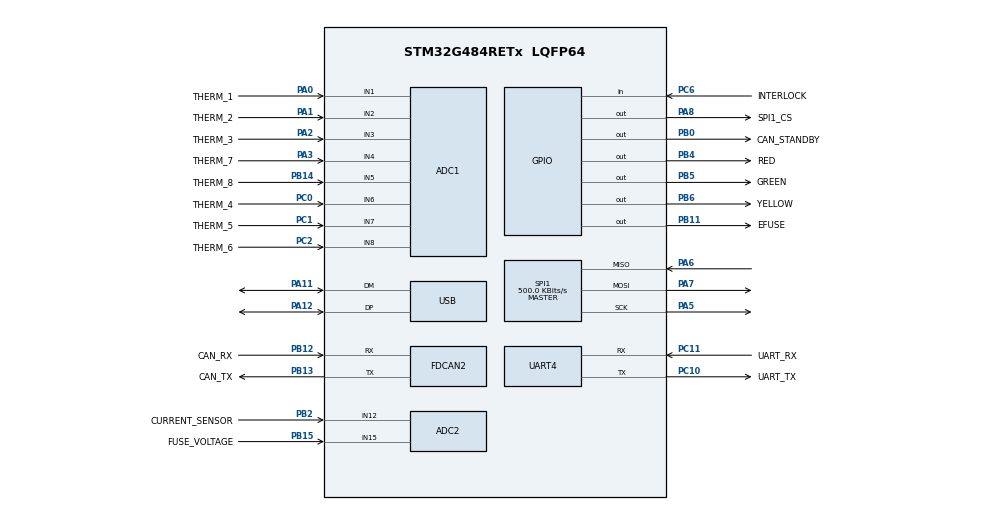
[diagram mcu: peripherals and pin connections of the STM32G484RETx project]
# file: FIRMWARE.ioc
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ADC1.Channel-0\#ChannelRegularConversion=ADC_CHANNEL_1
ADC1.Channel-1\#ChannelRegularConversion=ADC_CHANNEL_2
ADC1.Channel-2\#ChannelRegularConversion=ADC_CHANNEL_3
ADC1.Channel-3\#ChannelRegularConversion=ADC_CHANNEL_4
ADC1.Channel-4\#ChannelRegularConversion=ADC_CHANNEL_5
ADC1.Channel-5\#ChannelRegularConversion=ADC_CHANNEL_6
ADC1.Channel-6\#ChannelRegularConversion=ADC_CHANNEL_7
ADC1.Channel-7\#ChannelRegularConversion=ADC_CHANNEL_8
ADC1.ClockPrescaler=ADC_CLOCK_ASYNC_DIV4
ADC1.ContinuousConvMode=ENABLE
ADC1.DMAContinuousRequests=ENABLE
ADC1.NbrOfConversion=8
ADC1.NbrOfConversionFlag=1
ADC1.OffsetNumber-0\#ChannelRegularConversion=ADC_OFFSET_NONE
ADC1.OffsetNumber-1\#ChannelRegularConversion=ADC_OFFSET_NONE
ADC1.OffsetNumber-2\#ChannelRegularConversion=ADC_OFFSET_NONE
ADC1.OffsetNumber-3\#ChannelRegularConversion=ADC_OFFSET_NONE
ADC1.OffsetNumber-4\#ChannelRegularConversion=ADC_OFFSET_NONE
ADC1.OffsetNumber-5\#ChannelRegularConversion=ADC_OFFSET_NONE
ADC1.OffsetNumber-6\#ChannelRegularConversion=ADC_OFFSET_NONE
ADC1.OffsetNumber-7\#ChannelRegularConversion=ADC_OFFSET_NONE
ADC1.Rank-0\#ChannelRegularConversion=1
ADC1.Rank-1\#ChannelRegularConversion=2
ADC1.Rank-2\#ChannelRegularConversion=3
ADC1.Rank-3\#ChannelRegularConversion=4
ADC1.Rank-4\#ChannelRegularConversion=5
ADC1.Rank-5\#ChannelRegularConversion=6
ADC1.Rank-6\#ChannelRegularConversion=7
ADC1.Rank-7\#ChannelRegularConversion=8
ADC1.SamplingTime-0\#ChannelRegularConversion=ADC_SAMPLETIME_247CYCLES_5
ADC1.SamplingTime-1\#ChannelRegularConversion=ADC_SAMPLETIME_247CYCLES_5
ADC1.SamplingTime-2\#ChannelRegularConversion=ADC_SAMPLETIME_247CYCLES_5
ADC1.SamplingTime-3\#ChannelRegularConversion=ADC_SAMPLETIME_247CYCLES_5
ADC1.SamplingTime-4\#ChannelRegularConversion=ADC_SAMPLETIME_2CYCLES_5
ADC1.SamplingTime-5\#ChannelRegularConversion=ADC_SAMPLETIME_247CYCLES_5
ADC1.SamplingTime-6\#ChannelRegularConversion=ADC_SAMPLETIME_247CYCLES_5
ADC1.SamplingTime-7\#ChannelRegularConversion=ADC_SAMPLETIME_247CYCLES_5
ADC1.master=1
ADC2.Channel-0\#ChannelRegularConversion=ADC_CHANNEL_15
ADC2.Channel-1\#ChannelRegularConversion=ADC_CHANNEL_12
ADC2.ClockPrescaler=ADC_CLOCK_ASYNC_DIV4
ADC2.ContinuousConvMode=ENABLE
ADC2.DMAContinuousRequests=ENABLE
ADC2.NbrOfConversion=2
ADC2.NbrOfConversionFlag=1
ADC2.OffsetNumber-0\#ChannelRegularConversion=ADC_OFFSET_NONE
ADC2.OffsetNumber-1\#ChannelRegularConversion=ADC_OFFSET_NONE
ADC2.Rank-0\#ChannelRegularConversion=1
ADC2.Rank-1\#ChannelRegularConversion=2
ADC2.SamplingTime-0\#ChannelRegularConversion=ADC_SAMPLETIME_247CYCLES_5
ADC2.SamplingTime-1\#ChannelRegularConversion=ADC_SAMPLETIME_247CYCLES_5
Dma.ADC1.0.Direction=DMA_PERIPH_TO_MEMORY
Dma.ADC1.0.EventEnable=DISABLE
Dma.ADC1.0.Instance=DMA1_Channel1
Dma.ADC1.0.MemDataAlignment=DMA_MDATAALIGN_HALFWORD
Dma.ADC1.0.MemInc=DMA_MINC_ENABLE
Dma.ADC1.0.Mode=DMA_CIRCULAR
Dma.ADC1.0.PeriphDataAlignment=DMA_PDATAALIGN_HALFWORD
Dma.ADC1.0.PeriphInc=DMA_PINC_DISABLE
Dma.ADC1.0.Polarity=HAL_DMAMUX_REQ_GEN_RISING
Dma.ADC1.0.Priority=DMA_PRIORITY_MEDIUM
Dma.ADC1.0.RequestNumber=1
Dma.ADC1.0.SignalID=NONE
Dma.ADC1.0.SyncEnable=DISABLE
Dma.ADC1.0.SyncPolarity=HAL_DMAMUX_SYNC_NO_EVENT
Dma.ADC1.0.SyncRequestNumber=1
Dma.ADC1.0.SyncSignalID=NONE
Dma.ADC2.1.Direction=DMA_PERIPH_TO_MEMORY
Dma.ADC2.1.EventEnable=DISABLE
Dma.ADC2.1.Instance=DMA2_Channel1
Dma.ADC2.1.MemDataAlignment=DMA_MDATAALIGN_WORD
Dma.ADC2.1.MemInc=DMA_MINC_ENABLE
Dma.ADC2.1.Mode=DMA_CIRCULAR
Dma.ADC2.1.PeriphDataAlignment=DMA_PDATAALIGN_WORD
Dma.ADC2.1.PeriphInc=DMA_PINC_DISABLE
Dma.ADC2.1.Polarity=HAL_DMAMUX_REQ_GEN_RISING
Dma.ADC2.1.Priority=DMA_PRIORITY_LOW
Dma.ADC2.1.RequestNumber=1
Dma.ADC2.1.SignalID=NONE
Dma.ADC2.1.SyncEnable=DISABLE
Dma.ADC2.1.SyncPolarity=HAL_DMAMUX_SYNC_NO_EVENT
Dma.ADC2.1.SyncRequestNumber=1
Dma.ADC2.1.SyncSignalID=NONE
Dma.Request0=ADC1
Dma.Request1=ADC2
FDCAN2.CalculateBaudRateNominal=1000000
FDCAN2.CalculateTimeBitNominal=1000
FDCAN2.CalculateTimeQuantumNominal=62.5
FDCAN2.DataSyncJumpWidth=2
FDCAN2.NominalPrescaler=4
FDCAN2.NominalSyncJumpWidth=2
FDCAN2.NominalTimeSeg1=11
FDCAN2.NominalTimeSeg2=4
FREERTOS.Tasks01=defaultTask,8,512,StartDefaultTask,Default,NULL,Dynamic,NULL,NULL;ltc_task,24,512,start_ltc_function,As external,NULL,Static,ltc_taskBuffer,ltc_taskControlBlock;soc_update_task,16,512,start_soc_function,As external,NULL,Static,soc_update_taskBuffer,soc_update_taskControlBlock;balance_task,32,512,start_balance_function,As external,NULL,Static,balance_taskBuffer,balance_taskControlBlock;comm_err_task,40,512,start_comm_err_function,As external,NULL,Static,comm_err_taskBuffer,comm_err_taskControlBlock
FREERTOS.configENABLE_FPU=1
FREERTOS.configTOTAL_HEAP_SIZE=12000
FREERTOS.configUSE_NEWLIB_REENTRANT=1
Mcu.Family=STM32G4
Mcu.Name=STM32G484RETx
Mcu.Package=LQFP64
NVIC.ADC1_2_IRQn=true\:5\:0\:false\:false\:true\:true\:true\:true\:true
NVIC.DMA1_Channel1_IRQn=true\:5\:0\:false\:false\:true\:true\:false\:true\:true
NVIC.DMA2_Channel1_IRQn=true\:5\:0\:false\:false\:true\:false\:false\:true\:true
NVIC.FDCAN2_IT0_IRQn=true\:5\:0\:false\:false\:true\:true\:true\:true\:true
NVIC.FDCAN2_IT1_IRQn=true\:5\:0\:false\:false\:true\:true\:true\:true\:true
NVIC.PriorityGroup=NVIC_PRIORITYGROUP_4
NVIC.TIM1_UP_TIM16_IRQn=true\:15\:0\:false\:false\:true\:false\:false\:true\:true
NVIC.TIM3_IRQn=true\:5\:0\:false\:false\:true\:true\:true\:true\:true
NVIC.TIM6_DAC_IRQn=true\:5\:0\:false\:false\:true\:true\:true\:true\:true
NVIC.TimeBase=TIM1_UP_TIM16_IRQn
NVIC.TimeBaseIP=TIM16
NVIC.UART4_IRQn=true\:5\:0\:false\:false\:true\:true\:true\:true\:true
NVIC.USB_LP_IRQn=true\:5\:0\:false\:false\:true\:true\:false\:true\:true
PA0.GPIO_Label=THERM_1
PA0.Mode=IN1-Single-Ended
PA0.Signal=ADC1_IN1
PA1.GPIO_Label=THERM_2
PA1.Mode=IN2-Single-Ended
PA1.Signal=ADC1_IN2
PA11.Mode=Device
PA11.Signal=USB_DM
PA12.Mode=Device
PA12.Signal=USB_DP
PA13.Mode=Serial_Wire
PA13.Signal=SYS_JTMS-SWDIO
PA14.Mode=Serial_Wire
PA14.Signal=SYS_JTCK-SWCLK
PA2.GPIO_Label=THERM_3
PA2.Mode=IN3-Single-Ended
PA2.Signal=ADC1_IN3
PA3.GPIO_Label=THERM_7
PA3.Mode=IN4-Single-Ended
PA3.Signal=ADC1_IN4
PA5.GPIO_Speed=GPIO_SPEED_FREQ_VERY_HIGH
PA5.Mode=Full_Duplex_Master
PA5.Signal=SPI1_SCK
PA6.GPIO_PuPd=GPIO_PULLUP
PA6.GPIO_Speed=GPIO_SPEED_FREQ_VERY_HIGH
PA6.Mode=Full_Duplex_Master
PA6.Signal=SPI1_MISO
PA7.GPIO_Speed=GPIO_SPEED_FREQ_VERY_HIGH
PA7.Mode=Full_Duplex_Master
PA7.Signal=SPI1_MOSI
PA8.GPIO_Label=SPI1_CS
PA8.GPIO_Speed=GPIO_SPEED_FREQ_VERY_HIGH
PA8.Signal=GPIO_Output
PB0.GPIO_Label=CAN_STANDBY
PB0.Signal=GPIO_Output
PB11.GPIO_Label=EFUSE
PB11.GPIO_Speed=GPIO_SPEED_FREQ_VERY_HIGH
PB11.Signal=GPIO_Output
PB12.GPIO_Label=CAN_RX
PB12.Mode=FDCAN_Activate
PB12.Signal=FDCAN2_RX
PB13.GPIO_Label=CAN_TX
PB13.Mode=FDCAN_Activate
PB13.Signal=FDCAN2_TX
PB14.GPIO_Label=THERM_8
PB14.Mode=IN5-Single-Ended
PB14.Signal=ADC1_IN5
PB15.GPIO_Label=FUSE_VOLTAGE
PB15.Mode=IN15-Single-Ended
PB15.Signal=ADC2_IN15
PB2.GPIO_Label=CURRENT_SENSOR
PB2.Mode=IN12-Single-Ended
PB2.Signal=ADC2_IN12
PB4.GPIO_Label=RED
PB4.GPIO_Speed=GPIO_SPEED_FREQ_VERY_HIGH
PB4.Signal=GPIO_Output
PB5.GPIO_Label=GREEN
PB5.GPIO_Speed=GPIO_SPEED_FREQ_VERY_HIGH
PB5.Signal=GPIO_Output
PB6.GPIO_Label=YELLOW
PB6.GPIO_Speed=GPIO_SPEED_FREQ_VERY_HIGH
PB6.Signal=GPIO_Output
PC0.GPIO_Label=THERM_4
PC0.Mode=IN6-Single-Ended
PC0.Signal=ADC1_IN6
PC1.GPIO_Label=THERM_5
PC1.Mode=IN7-Single-Ended
PC1.Signal=ADC1_IN7
PC10.GPIO_Label=UART_TX
PC10.Mode=Asynchronous
PC10.Signal=UART4_TX
PC11.GPIO_Label=UART_RX
PC11.Mode=Asynchronous
PC11.Signal=UART4_RX
PC2.GPIO_Label=THERM_6
PC2.Mode=IN8-Single-Ended
PC2.Signal=ADC1_IN8
PC6.GPIO_Label=INTERLOCK
PC6.GPIO_PuPd=GPIO_PULLUP
PC6.Signal=GPIO_Input
ProjectManager.HeapSize=0x200
ProjectManager.StackSize=0x400
ProjectManager.TargetToolchain=CMake
RCC.ADC12Freq_Value=64000000
RCC.ADC345Freq_Value=64000000
RCC.AHBFreq_Value=64000000
RCC.APB1Freq_Value=64000000
RCC.APB1TimFreq_Value=64000000
RCC.APB2CLKDivider=RCC_HCLK_DIV2
RCC.APB2Freq_Value=32000000
RCC.APB2TimFreq_Value=64000000
RCC.CK48CLockSelection=RCC_USBCLKSOURCE_HSI48
RCC.CortexFreq_Value=64000000
RCC.EXTERNAL_CLOCK_VALUE=12288000
RCC.FDCANCLockSelection=RCC_FDCANCLKSOURCE_PLL
RCC.HCLKFreq_Value=64000000
RCC.HSE_Timout=1000
RCC.HSE_VALUE=32000000
RCC.HSI48_VALUE=48000000
RCC.HSI_VALUE=16000000
RCC.LSE_VALUE=32768
RCC.SYSCLKFreq_VALUE=64000000
RCC.SYSCLKSource=RCC_SYSCLKSOURCE_PLLCLK
RCC.USBFreq_Value=48000000
RCC.VCOOutputFreq_Value=128000000
SPI1.BaudRatePrescaler=SPI_BAUDRATEPRESCALER_64
SPI1.CLKPhase=SPI_PHASE_2EDGE
SPI1.CLKPolarity=SPI_POLARITY_HIGH
SPI1.CalculateBaudRate=500.0 KBits/s
SPI1.DataSize=SPI_DATASIZE_8BIT
SPI1.Direction=SPI_DIRECTION_2LINES
SPI1.Mode=SPI_MODE_MASTER
SPI1.VirtualType=VM_MASTER
TIM3.PeriodNoDither=49
TIM3.Prescaler=6399
TIM6.PeriodNoDither=9
TIM6.Prescaler=2399
TIM6.TIM_MasterOutputTrigger=TIM_TRGO_UPDATE
TIM8.PeriodNoDither=49
TIM8.Prescaler=95
TIM8.TIM_MasterOutputTrigger=TIM_TRGO_UPDATE
TIM8.TIM_MasterOutputTrigger2=TIM_TRGO2_UPDATE
USB_DEVICE.CLASS_NAME_FS=CDC
USB_DEVICE.VirtualMode=Cdc
USB_DEVICE.VirtualModeFS=Cdc_FS
VP_FREERTOS_VS_CMSIS_V2.Mode=CMSIS_V2
VP_RTC_VS_RTC_Activate.Mode=RTC_Enabled
VP_RTC_VS_RTC_Calendar.Mode=RTC_Calendar
VP_SYS_VS_DBSignals.Mode=DisableDeadBatterySignals
VP_SYS_VS_tim16.Mode=TIM16
VP_TIM3_VS_ClockSourceINT.Mode=Internal
VP_TIM6_VS_ClockSourceINT.Mode=Enable_Timer
VP_TIM8_VS_ClockSourceINT.Mode=Internal
VP_USB_DEVICE_VS_USB_DEVICE_CDC_FS.Mode=CDC_FS
board=custom

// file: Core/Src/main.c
/* USER CODE BEGIN Header */
/**
  ******************************************************************************
  * @file           : main.c
  * @brief          : Main program body
  ******************************************************************************
  * @attention
  *
  * Copyright (c) 2026 STMicroelectronics.
  * All rights reserved.
  *
  * This software is licensed under terms that can be found in the LICENSE file
  * in the root directory of this software component.
  * If no LICENSE file comes with this software, it is provided AS-IS.
  *
  ******************************************************************************
  */
/* USER CODE END Header */
#include "main.h"
#include "cmsis_os.h"
#include "adc.h"
#include "dma.h"
#include "fdcan.h"
#include "rtc.h"
#include "spi.h"
#include "tim.h"
#include "usart.h"
#include "usb_device.h"
#include "gpio.h"

void SystemClock_Config(void);
void MX_FREERTOS_Init(void);

int main(void)
{

  /* MCU Configuration--------------------------------------------------------*/

  /* Reset of all peripherals, Initializes the Flash interface and the Systick. */
  HAL_Init();

  /* Configure the system clock */
  SystemClock_Config();

  /* Initialize all configured peripherals */
  MX_GPIO_Init();
  MX_DMA_Init();
  MX_ADC1_Init();
  MX_ADC2_Init();
  MX_FDCAN2_Init();
  MX_SPI1_Init();
  MX_UART4_Init();
  MX_RTC_Init();
  MX_TIM3_Init();
  MX_TIM6_Init();
  MX_TIM8_Init();

  /* Init scheduler */
  osKernelInitialize();  /* Call init function for freertos objects (in cmsis_os2.c) */
  MX_FREERTOS_Init();

  /* Start scheduler */
  osKernelStart();

  /* We should never get here as control is now taken by the scheduler */

  /* Infinite loop */
  while (1)
  {

  }
}

void SystemClock_Config(void)
{
  RCC_OscInitTypeDef RCC_OscInitStruct = {0};
  RCC_ClkInitTypeDef RCC_ClkInitStruct = {0};

  /** Configure the main internal regulator output voltage
  */
  HAL_PWREx_ControlVoltageScaling(PWR_REGULATOR_VOLTAGE_SCALE1);

  /** Initializes the RCC Oscillators according to the specified parameters
  * in the RCC_OscInitTypeDef structure.
  */
  RCC_OscInitStruct.OscillatorType = RCC_OSCILLATORTYPE_HSI48|RCC_OSCILLATORTYPE_LSI
                              |RCC_OSCILLATORTYPE_HSE;
  RCC_OscInitStruct.HSEState = RCC_HSE_BYPASS;
  RCC_OscInitStruct.LSIState = RCC_LSI_ON;
  RCC_OscInitStruct.HSI48State = RCC_HSI48_ON;
  RCC_OscInitStruct.PLL.PLLState = RCC_PLL_ON;
  RCC_OscInitStruct.PLL.PLLSource = RCC_PLLSOURCE_HSE;
  RCC_OscInitStruct.PLL.PLLM = RCC_PLLM_DIV2;
  RCC_OscInitStruct.PLL.PLLN = 8;
  RCC_OscInitStruct.PLL.PLLP = RCC_PLLP_DIV2;
  RCC_OscInitStruct.PLL.PLLQ = RCC_PLLQ_DIV2;
  RCC_OscInitStruct.PLL.PLLR = RCC_PLLR_DIV2;
  if (HAL_RCC_OscConfig(&RCC_OscInitStruct) != HAL_OK)
  {
    Error_Handler();
  }

  /** Initializes the CPU, AHB and APB buses clocks
  */
  RCC_ClkInitStruct.ClockType = RCC_CLOCKTYPE_HCLK|RCC_CLOCKTYPE_SYSCLK
                              |RCC_CLOCKTYPE_PCLK1|RCC_CLOCKTYPE_PCLK2;
  RCC_ClkInitStruct.SYSCLKSource = RCC_SYSCLKSOURCE_PLLCLK;
  RCC_ClkInitStruct.AHBCLKDivider = RCC_SYSCLK_DIV1;
  RCC_ClkInitStruct.APB1CLKDivider = RCC_HCLK_DIV2;
  RCC_ClkInitStruct.APB2CLKDivider = RCC_HCLK_DIV1;

  if (HAL_RCC_ClockConfig(&RCC_ClkInitStruct, FLASH_LATENCY_2) != HAL_OK)
  {
    Error_Handler();
  }
}

void HAL_TIM_PeriodElapsedCallback(TIM_HandleTypeDef *htim)
{
  if (htim->Instance == TIM16)
  {
    HAL_IncTick();
  }
}

void Error_Handler(void)
{
  __disable_irq();
  while (1)
  {
  }
}

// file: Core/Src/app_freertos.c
/* USER CODE BEGIN Header */
/**
  ******************************************************************************
  * File Name          : app_freertos.c
  * Description        : Code for freertos applications
  ******************************************************************************
  * @attention
  *
  * Copyright (c) 2026 STMicroelectronics.
  * All rights reserved.
  *
  * This software is licensed under terms that can be found in the LICENSE file
  * in the root directory of this software component.
  * If no LICENSE file comes with this software, it is provided AS-IS.
  *
  ******************************************************************************
  */
/* USER CODE END Header */

#include "FreeRTOS.h"
#include "task.h"
#include "main.h"
#include "cmsis_os.h"

#include "usb_device.h"

typedef StaticTask_t osStaticThreadDef_t;

/* Definitions for defaultTask */
osThreadId_t defaultTaskHandle;
const osThreadAttr_t defaultTask_attributes = {
  .name = "defaultTask",
  .priority = (osPriority_t) osPriorityLow,
  .stack_size = 512 * 4
};
/* Definitions for ltc_task */
osThreadId_t ltc_taskHandle;
uint32_t ltc_taskBuffer[ 512 ];
osStaticThreadDef_t ltc_taskControlBlock;
const osThreadAttr_t ltc_task_attributes = {
  .name = "ltc_task",
  .stack_mem = &ltc_taskBuffer[0],
  .stack_size = sizeof(ltc_taskBuffer),
  .cb_mem = &ltc_taskControlBlock,
  .cb_size = sizeof(ltc_taskControlBlock),
  .priority = (osPriority_t) osPriorityNormal,
};
/* Definitions for soc_update_task */
osThreadId_t soc_update_taskHandle;
uint32_t soc_update_taskBuffer[ 512 ];
osStaticThreadDef_t soc_update_taskControlBlock;
const osThreadAttr_t soc_update_task_attributes = {
  .name = "soc_update_task",
  .stack_mem = &soc_update_taskBuffer[0],
  .stack_size = sizeof(soc_update_taskBuffer),
  .cb_mem = &soc_update_taskControlBlock,
  .cb_size = sizeof(soc_update_taskControlBlock),
  .priority = (osPriority_t) osPriorityBelowNormal,
};
/* Definitions for balance_task */
osThreadId_t balance_taskHandle;
uint32_t balance_taskBuffer[ 512 ];
osStaticThreadDef_t balance_taskControlBlock;
const osThreadAttr_t balance_task_attributes = {
  .name = "balance_task",
  .stack_mem = &balance_taskBuffer[0],
  .stack_size = sizeof(balance_taskBuffer),
  .cb_mem = &balance_taskControlBlock,
  .cb_size = sizeof(balance_taskControlBlock),
  .priority = (osPriority_t) osPriorityAboveNormal,
};
/* Definitions for comm_err_task */
osThreadId_t comm_err_taskHandle;
uint32_t comm_err_taskBuffer[ 512 ];
osStaticThreadDef_t comm_err_taskControlBlock;
const osThreadAttr_t comm_err_task_attributes = {
  .name = "comm_err_task",
  .stack_mem = &comm_err_taskBuffer[0],
  .stack_size = sizeof(comm_err_taskBuffer),
  .cb_mem = &comm_err_taskControlBlock,
  .cb_size = sizeof(comm_err_taskControlBlock),
  .priority = (osPriority_t) osPriorityHigh,
};

void StartDefaultTask(void *argument);
extern void start_ltc_function(void *argument);
extern void start_soc_function(void *argument);
extern void start_balance_function(void *argument);
extern void start_comm_err_function(void *argument);

void MX_FREERTOS_Init(void); /* (MISRA C 2004 rule 8.1) */

void MX_FREERTOS_Init(void) {

  /* Create the thread(s) */
  /* creation of defaultTask */
  defaultTaskHandle = osThreadNew(StartDefaultTask, NULL, &defaultTask_attributes);

  /* creation of ltc_task */
  ltc_taskHandle = osThreadNew(start_ltc_function, NULL, &ltc_task_attributes);

  /* creation of soc_update_task */
  soc_update_taskHandle = osThreadNew(start_soc_function, NULL, &soc_update_task_attributes);

  /* creation of balance_task */
  balance_taskHandle = osThreadNew(start_balance_function, NULL, &balance_task_attributes);

  /* creation of comm_err_task */
  comm_err_taskHandle = osThreadNew(start_comm_err_function, NULL, &comm_err_task_attributes);

}

void StartDefaultTask(void *argument)
{
  /* init code for USB_Device */
  MX_USB_Device_Init();
  for(;;)
  {
    osDelay(1);
  }
}
